VERSION 5.7 ;
BUSBITCHARS "[]" ;
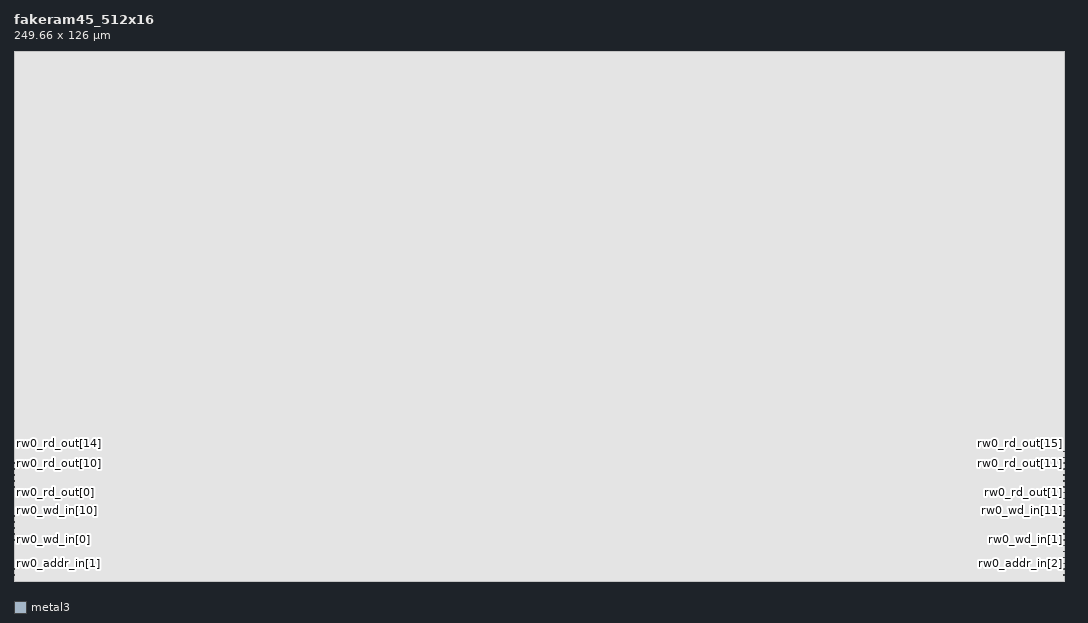
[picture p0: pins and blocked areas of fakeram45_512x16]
MACRO fakeram45_512x16
  FOREIGN fakeram45_512x16 0 0 ;
  SYMMETRY X Y R90 ;
  SIZE 249.660 BY 126.000 ;
  CLASS BLOCK ;
  PIN rw0_clk
    DIRECTION INPUT ;
    USE SIGNAL ;
    SHAPE ABUTMENT ;
    PORT
      LAYER metal3 ;
      RECT 0.000 1.330 0.140 1.470 ;
    END
  END rw0_clk
  PIN rw0_ce_in
    DIRECTION INPUT ;
    USE SIGNAL ;
    SHAPE ABUTMENT ;
    PORT
      LAYER metal3 ;
      RECT 249.520 1.330 249.660 1.470 ;
    END
  END rw0_ce_in
  PIN rw0_we_in
    DIRECTION INPUT ;
    USE SIGNAL ;
    SHAPE ABUTMENT ;
    PORT
      LAYER metal3 ;
      RECT 0.000 2.730 0.140 2.870 ;
    END
  END rw0_we_in
  PIN rw0_addr_in[0]
    DIRECTION INPUT ;
    USE SIGNAL ;
    SHAPE ABUTMENT ;
    PORT
      LAYER metal3 ;
      RECT 249.520 2.730 249.660 2.870 ;
    END
  END rw0_addr_in[0]
  PIN rw0_addr_in[1]
    DIRECTION INPUT ;
    USE SIGNAL ;
    SHAPE ABUTMENT ;
    PORT
      LAYER metal3 ;
      RECT 0.000 4.130 0.140 4.270 ;
    END
  END rw0_addr_in[1]
  PIN rw0_addr_in[2]
    DIRECTION INPUT ;
    USE SIGNAL ;
    SHAPE ABUTMENT ;
    PORT
      LAYER metal3 ;
      RECT 249.520 4.130 249.660 4.270 ;
    END
  END rw0_addr_in[2]
  PIN rw0_addr_in[3]
    DIRECTION INPUT ;
    USE SIGNAL ;
    SHAPE ABUTMENT ;
    PORT
      LAYER metal3 ;
      RECT 0.000 5.530 0.140 5.670 ;
    END
  END rw0_addr_in[3]
  PIN rw0_addr_in[4]
    DIRECTION INPUT ;
    USE SIGNAL ;
    SHAPE ABUTMENT ;
    PORT
      LAYER metal3 ;
      RECT 249.520 5.530 249.660 5.670 ;
    END
  END rw0_addr_in[4]
  PIN rw0_addr_in[5]
    DIRECTION INPUT ;
    USE SIGNAL ;
    SHAPE ABUTMENT ;
    PORT
      LAYER metal3 ;
      RECT 0.000 6.930 0.140 7.070 ;
    END
  END rw0_addr_in[5]
  PIN rw0_addr_in[6]
    DIRECTION INPUT ;
    USE SIGNAL ;
    SHAPE ABUTMENT ;
    PORT
      LAYER metal3 ;
      RECT 249.520 6.930 249.660 7.070 ;
    END
  END rw0_addr_in[6]
  PIN rw0_addr_in[7]
    DIRECTION INPUT ;
    USE SIGNAL ;
    SHAPE ABUTMENT ;
    PORT
      LAYER metal3 ;
      RECT 0.000 8.330 0.140 8.470 ;
    END
  END rw0_addr_in[7]
  PIN rw0_addr_in[8]
    DIRECTION INPUT ;
    USE SIGNAL ;
    SHAPE ABUTMENT ;
    PORT
      LAYER metal3 ;
      RECT 249.520 8.330 249.660 8.470 ;
    END
  END rw0_addr_in[8]
  PIN rw0_wd_in[0]
    DIRECTION INPUT ;
    USE SIGNAL ;
    SHAPE ABUTMENT ;
    PORT
      LAYER metal3 ;
      RECT 0.000 9.730 0.140 9.870 ;
    END
  END rw0_wd_in[0]
  PIN rw0_wd_in[1]
    DIRECTION INPUT ;
    USE SIGNAL ;
    SHAPE ABUTMENT ;
    PORT
      LAYER metal3 ;
      RECT 249.520 9.730 249.660 9.870 ;
    END
  END rw0_wd_in[1]
  PIN rw0_wd_in[2]
    DIRECTION INPUT ;
    USE SIGNAL ;
    SHAPE ABUTMENT ;
    PORT
      LAYER metal3 ;
      RECT 0.000 11.130 0.140 11.270 ;
    END
  END rw0_wd_in[2]
  PIN rw0_wd_in[3]
    DIRECTION INPUT ;
    USE SIGNAL ;
    SHAPE ABUTMENT ;
    PORT
      LAYER metal3 ;
      RECT 249.520 11.130 249.660 11.270 ;
    END
  END rw0_wd_in[3]
  PIN rw0_wd_in[4]
    DIRECTION INPUT ;
    USE SIGNAL ;
    SHAPE ABUTMENT ;
    PORT
      LAYER metal3 ;
      RECT 0.000 12.530 0.140 12.670 ;
    END
  END rw0_wd_in[4]
  PIN rw0_wd_in[5]
    DIRECTION INPUT ;
    USE SIGNAL ;
    SHAPE ABUTMENT ;
    PORT
      LAYER metal3 ;
      RECT 249.520 12.530 249.660 12.670 ;
    END
  END rw0_wd_in[5]
  PIN rw0_wd_in[6]
    DIRECTION INPUT ;
    USE SIGNAL ;
    SHAPE ABUTMENT ;
    PORT
      LAYER metal3 ;
      RECT 0.000 13.930 0.140 14.070 ;
    END
  END rw0_wd_in[6]
  PIN rw0_wd_in[7]
    DIRECTION INPUT ;
    USE SIGNAL ;
    SHAPE ABUTMENT ;
    PORT
      LAYER metal3 ;
      RECT 249.520 13.930 249.660 14.070 ;
    END
  END rw0_wd_in[7]
  PIN rw0_wd_in[8]
    DIRECTION INPUT ;
    USE SIGNAL ;
    SHAPE ABUTMENT ;
    PORT
      LAYER metal3 ;
      RECT 0.000 15.330 0.140 15.470 ;
    END
  END rw0_wd_in[8]
  PIN rw0_wd_in[9]
    DIRECTION INPUT ;
    USE SIGNAL ;
    SHAPE ABUTMENT ;
    PORT
      LAYER metal3 ;
      RECT 249.520 15.330 249.660 15.470 ;
    END
  END rw0_wd_in[9]
  PIN rw0_wd_in[10]
    DIRECTION INPUT ;
    USE SIGNAL ;
    SHAPE ABUTMENT ;
    PORT
      LAYER metal3 ;
      RECT 0.000 16.730 0.140 16.870 ;
    END
  END rw0_wd_in[10]
  PIN rw0_wd_in[11]
    DIRECTION INPUT ;
    USE SIGNAL ;
    SHAPE ABUTMENT ;
    PORT
      LAYER metal3 ;
      RECT 249.520 16.730 249.660 16.870 ;
    END
  END rw0_wd_in[11]
  PIN rw0_wd_in[12]
    DIRECTION INPUT ;
    USE SIGNAL ;
    SHAPE ABUTMENT ;
    PORT
      LAYER metal3 ;
      RECT 0.000 18.130 0.140 18.270 ;
    END
  END rw0_wd_in[12]
  PIN rw0_wd_in[13]
    DIRECTION INPUT ;
    USE SIGNAL ;
    SHAPE ABUTMENT ;
    PORT
      LAYER metal3 ;
      RECT 249.520 18.130 249.660 18.270 ;
    END
  END rw0_wd_in[13]
  PIN rw0_wd_in[14]
    DIRECTION INPUT ;
    USE SIGNAL ;
    SHAPE ABUTMENT ;
    PORT
      LAYER metal3 ;
      RECT 0.000 19.530 0.140 19.670 ;
    END
  END rw0_wd_in[14]
  PIN rw0_wd_in[15]
    DIRECTION INPUT ;
    USE SIGNAL ;
    SHAPE ABUTMENT ;
    PORT
      LAYER metal3 ;
      RECT 249.520 19.530 249.660 19.670 ;
    END
  END rw0_wd_in[15]
  PIN rw0_rd_out[0]
    DIRECTION OUTPUT ;
    USE SIGNAL ;
    SHAPE ABUTMENT ;
    PORT
      LAYER metal3 ;
      RECT 0.000 20.930 0.140 21.070 ;
    END
  END rw0_rd_out[0]
  PIN rw0_rd_out[1]
    DIRECTION OUTPUT ;
    USE SIGNAL ;
    SHAPE ABUTMENT ;
    PORT
      LAYER metal3 ;
      RECT 249.520 20.930 249.660 21.070 ;
    END
  END rw0_rd_out[1]
  PIN rw0_rd_out[2]
    DIRECTION OUTPUT ;
    USE SIGNAL ;
    SHAPE ABUTMENT ;
    PORT
      LAYER metal3 ;
      RECT 0.000 22.330 0.140 22.470 ;
    END
  END rw0_rd_out[2]
  PIN rw0_rd_out[3]
    DIRECTION OUTPUT ;
    USE SIGNAL ;
    SHAPE ABUTMENT ;
    PORT
      LAYER metal3 ;
      RECT 249.520 22.330 249.660 22.470 ;
    END
  END rw0_rd_out[3]
  PIN rw0_rd_out[4]
    DIRECTION OUTPUT ;
    USE SIGNAL ;
    SHAPE ABUTMENT ;
    PORT
      LAYER metal3 ;
      RECT 0.000 23.730 0.140 23.870 ;
    END
  END rw0_rd_out[4]
  PIN rw0_rd_out[5]
    DIRECTION OUTPUT ;
    USE SIGNAL ;
    SHAPE ABUTMENT ;
    PORT
      LAYER metal3 ;
      RECT 249.520 23.730 249.660 23.870 ;
    END
  END rw0_rd_out[5]
  PIN rw0_rd_out[6]
    DIRECTION OUTPUT ;
    USE SIGNAL ;
    SHAPE ABUTMENT ;
    PORT
      LAYER metal3 ;
      RECT 0.000 25.130 0.140 25.270 ;
    END
  END rw0_rd_out[6]
  PIN rw0_rd_out[7]
    DIRECTION OUTPUT ;
    USE SIGNAL ;
    SHAPE ABUTMENT ;
    PORT
      LAYER metal3 ;
      RECT 249.520 25.130 249.660 25.270 ;
    END
  END rw0_rd_out[7]
  PIN rw0_rd_out[8]
    DIRECTION OUTPUT ;
    USE SIGNAL ;
    SHAPE ABUTMENT ;
    PORT
      LAYER metal3 ;
      RECT 0.000 26.530 0.140 26.670 ;
    END
  END rw0_rd_out[8]
  PIN rw0_rd_out[9]
    DIRECTION OUTPUT ;
    USE SIGNAL ;
    SHAPE ABUTMENT ;
    PORT
      LAYER metal3 ;
      RECT 249.520 26.530 249.660 26.670 ;
    END
  END rw0_rd_out[9]
  PIN rw0_rd_out[10]
    DIRECTION OUTPUT ;
    USE SIGNAL ;
    SHAPE ABUTMENT ;
    PORT
      LAYER metal3 ;
      RECT 0.000 27.930 0.140 28.070 ;
    END
  END rw0_rd_out[10]
  PIN rw0_rd_out[11]
    DIRECTION OUTPUT ;
    USE SIGNAL ;
    SHAPE ABUTMENT ;
    PORT
      LAYER metal3 ;
      RECT 249.520 27.930 249.660 28.070 ;
    END
  END rw0_rd_out[11]
  PIN rw0_rd_out[12]
    DIRECTION OUTPUT ;
    USE SIGNAL ;
    SHAPE ABUTMENT ;
    PORT
      LAYER metal3 ;
      RECT 0.000 29.330 0.140 29.470 ;
    END
  END rw0_rd_out[12]
  PIN rw0_rd_out[13]
    DIRECTION OUTPUT ;
    USE SIGNAL ;
    SHAPE ABUTMENT ;
    PORT
      LAYER metal3 ;
      RECT 249.520 29.330 249.660 29.470 ;
    END
  END rw0_rd_out[13]
  PIN rw0_rd_out[14]
    DIRECTION OUTPUT ;
    USE SIGNAL ;
    SHAPE ABUTMENT ;
    PORT
      LAYER metal3 ;
      RECT 0.000 30.730 0.140 30.870 ;
    END
  END rw0_rd_out[14]
  PIN rw0_rd_out[15]
    DIRECTION OUTPUT ;
    USE SIGNAL ;
    SHAPE ABUTMENT ;
    PORT
      LAYER metal3 ;
      RECT 249.520 30.730 249.660 30.870 ;
    END
  END rw0_rd_out[15]
  OBS
    LAYER metal1 ;
      RECT 0.000 0.000 249.660 126.000 ;
    LAYER metal2 ;
      RECT 0.000 0.000 249.660 126.000 ;
    LAYER metal3 ;
      RECT 0.000 0.000 249.660 126.000 ;
    LAYER metal4 ;
      RECT 0.000 0.000 249.660 126.000 ;
  END
END fakeram45_512x16
END LIBRARY
